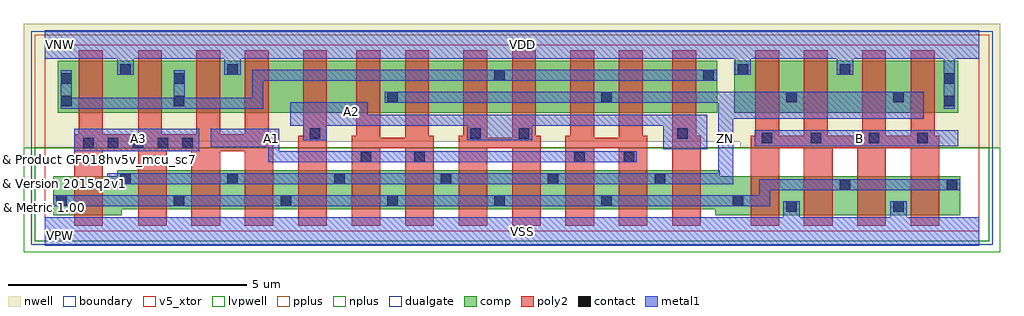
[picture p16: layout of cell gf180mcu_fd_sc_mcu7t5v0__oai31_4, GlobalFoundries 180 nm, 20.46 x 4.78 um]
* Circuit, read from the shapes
.subckt gf180mcu_fd_sc_mcu7t5v0__oai31_4 A1 A2 A3 B VDD VNW VSS ZN
XM1 ZN A3 n1 VSUBS nfet_05v0 w=0.82u l=0.6u m=4
XM2 ZN A2 n1 VSUBS nfet_05v0 w=0.82u l=0.6u m=4
XM3 n1 A1 ZN VSUBS nfet_05v0 w=0.82u l=0.6u m=4
XM4 VSS B n1 VSUBS nfet_05v0 w=0.82u l=0.6u m=4
XM5 VDD A3 n2 VNW pfet_05v0 w=1.095u l=0.5u m=3
XM6 n3 A3 VDD VNW pfet_05v0 w=1.095u l=0.5u
XM7 n4 A2 n3 VNW pfet_05v0 w=1.095u l=0.5u
XM8 ZN A1 n4 VNW pfet_05v0 w=1.095u l=0.5u
XM9 n5 A1 ZN VNW pfet_05v0 w=1.095u l=0.5u
XM10 n2 A2 n5 VNW pfet_05v0 w=1.095u l=0.5u
XM11 n6 A2 n2 VNW pfet_05v0 w=1.095u l=0.5u
XM12 ZN A1 n6 VNW pfet_05v0 w=1.095u l=0.5u
XM13 n7 A1 ZN VNW pfet_05v0 w=1.095u l=0.5u
XM14 n2 A2 n7 VNW pfet_05v0 w=1.095u l=0.5u
XM15 ZN B VDD VNW pfet_05v0 w=1.095u l=0.5u m=4
.ends

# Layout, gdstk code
import gdstk
lib = gdstk.Library(unit=1e-6, precision=1e-09)
def R(c, l, rs):  # rectangles x0, y0, x1, y1
    for r in rs: c.add(gdstk.rectangle(r[:2], r[2:], *l))
def A(c, l, x, y, w, h, nx, ny, dx, dy):  # array of equal rectangles
    R(c, l, [(x+i*dx, y+j*dy, x+i*dx+w, y+j*dy+h) for i in range(nx) for j in range(ny)])
def P(c, l, *ps):  # polygons
    for p in ps: c.add(gdstk.Polygon(p, *l))
boundary = (0, 0)
nwell = (21, 0)
comp = (22, 0)
poly2 = (30, 0)
pplus = (31, 0)
nplus = (32, 0)
contact = (33, 0)
metal1 = (34, 0)
dualgate = (55, 0)
v5_xtor = (112, 1)
lvpwell = (204, 0)

gf180mcu_fd_sc_mcu7t5v0_ = lib.new_cell('gf180mcu_fd_sc_mcu7t5v0__oai31_4')
R(gf180mcu_fd_sc_mcu7t5v0_, boundary, [(0,0,19.6,3.92)])
P(gf180mcu_fd_sc_mcu7t5v0_, nwell, [(-0.43,1.76),(-0.43,4.35),(20.03,4.35),(20.03,1.76),(14.58,1.76),(14.58,1.885),(1.095,1.885),(1.095,1.76)])
R(gf180mcu_fd_sc_mcu7t5v0_, comp, [(0.28,2.485,14.1,3.58), (14.46,2.485,19.15,3.58)])
P(gf180mcu_fd_sc_mcu7t5v0_, comp, [(0.18,0.34),(0.18,1.16),(1.52,1.16),(1.52,1.285),(14.16,1.285),(14.16,1.16),(19.2,1.16),(19.2,0.34),(14.06,0.34),(14.06,0.465),(1.62,0.465),(1.62,0.34)])
P(gf180mcu_fd_sc_mcu7t5v0_, poly2, [(0.62,0.12),(0.62,2.04),(0.72,2.04),(0.72,3.8),(1.22,3.8),(1.22,2.04),(1.96,2.04),(1.96,3.8),(2.46,3.8),(2.46,2.04),(3.18,2.04),(3.18,3.8),(3.68,3.8),(3.68,2.04),(4.2,2.04),(4.2,3.8),(4.7,3.8),(4.7,2.04),(4.8,2.04),(4.8,0.12),(4.2,0.12),(4.2,1.68),(3.68,1.68),(3.68,0.12),(3.08,0.12),(3.08,1.68),(2.56,1.68),(2.56,0.12),(1.96,0.12),(1.96,1.68),(1.22,1.68),(1.22,0.12)],
  [(5.32,0.12),(5.32,2.01),(5.42,2.01),(5.42,3.8),(5.92,3.8),(5.92,0.12)],
  [(6.44,0.12),(6.44,2.01),(6.54,2.01),(6.54,3.8),(7.04,3.8),(7.04,1.97),(7.56,1.97),(7.56,3.8),(8.06,3.8),(8.06,2.01),(8.16,2.01),(8.16,0.12),(7.56,0.12),(7.56,1.74),(7.04,1.74),(7.04,0.12)],
  [(8.68,0.12),(8.68,2.01),(8.78,2.01),(8.78,3.8),(9.28,3.8),(9.28,1.97),(9.8,1.97),(9.8,3.8),(10.3,3.8),(10.3,2.01),(10.4,2.01),(10.4,0.12),(9.8,0.12),(9.8,1.74),(9.28,1.74),(9.28,0.12)],
  [(10.92,0.12),(10.92,2.01),(11.02,2.01),(11.02,3.8),(11.52,3.8),(11.52,1.97),(12.04,1.97),(12.04,3.8),(12.54,3.8),(12.54,2.01),(12.64,2.01),(12.64,0.12),(12.04,0.12),(12.04,1.74),(11.52,1.74),(11.52,0.12)],
  [(13.16,0.12),(13.16,3.8),(13.66,3.8),(13.66,2.01),(13.76,2.01),(13.76,0.12)],
  [(14.8,0.12),(14.8,2.01),(14.9,2.01),(14.9,3.8),(15.4,3.8),(15.4,2.01),(15.92,2.01),(15.92,3.8),(16.42,3.8),(16.42,2.01),(17.14,2.01),(17.14,3.8),(17.64,3.8),(17.64,2.01),(18.16,2.01),(18.16,3.8),(18.66,3.8),(18.66,2.01),(18.76,2.01),(18.76,0.12),(18.16,0.12),(18.16,1.74),(17.64,1.74),(17.64,0.12),(17.04,0.12),(17.04,1.74),(16.52,1.74),(16.52,0.12),(15.92,0.12),(15.92,1.74),(15.4,1.74),(15.4,0.12)])
R(gf180mcu_fd_sc_mcu7t5v0_, pplus, [(-0.2,1.76,19.8,4.12)])
R(gf180mcu_fd_sc_mcu7t5v0_, nplus, [(-0.2,-0.2,19.8,1.76)])
A(gf180mcu_fd_sc_mcu7t5v0_, contact, 2.71, 0.535, 0.22, 0.22, 5, 1, 2.24, 0)
A(gf180mcu_fd_sc_mcu7t5v0_, contact, 1.59, 0.995, 0.22, 0.22, 6, 1, 2.24, 0)
A(gf180mcu_fd_sc_mcu7t5v0_, contact, 0.81, 1.75, 0.22, 0.22, 5, 1, 0.52, 0)
R(gf180mcu_fd_sc_mcu7t5v0_, contact, [(15.55,0.41,15.77,0.63), (17.79,0.41,18.01,0.63), (0.25,0.535,0.47,0.755), (14.43,0.535,14.65,0.755), (16.67,0.87,16.89,1.09), (18.91,0.87,19.13,1.09), (6.63,1.455,6.85,1.675), (7.75,1.455,7.97,1.675), (11.11,1.455,11.33,1.675), (12.14,1.455,12.36,1.675), (15.04,1.85,15.26,2.07), (16.06,1.85,16.28,2.07), (17.28,1.85,17.5,2.07), (18.3,1.85,18.52,2.07), (5.56,1.94,5.78,2.16), (8.92,1.94,9.14,2.16), (9.94,1.94,10.16,2.16), (13.26,1.94,13.48,2.16), (0.35,2.63,0.57,2.85), (2.71,2.63,2.93,2.85), (18.86,2.63,19.08,2.85), (7.19,2.705,7.41,2.925), (11.67,2.705,11.89,2.925), (15.55,2.705,15.77,2.925), (17.79,2.705,18.01,2.925), (0.35,3.1,0.57,3.32), (2.71,3.1,2.93,3.32), (18.86,3.1,19.08,3.32), (9.43,3.165,9.65,3.385), (13.81,3.165,14.03,3.385), (1.59,3.29,1.81,3.51), (3.83,3.29,4.05,3.51), (14.53,3.29,14.75,3.51), (16.67,3.29,16.89,3.51)])
R(gf180mcu_fd_sc_mcu7t5v0_, metal1, [(0.62,1.68,3.24,2.15), (14.89,1.785,19.15,2.12)])
P(gf180mcu_fd_sc_mcu7t5v0_, metal1, [(4.69,1.45),(4.69,1.77),(3.48,1.77),(3.48,2.15),(4.92,2.15),(4.92,1.68),(12.42,1.68),(12.42,1.45)],
  [(12.97,1.725),(12.97,2.22),(10.22,2.22),(10.22,1.91),(8.86,1.91),(8.86,2.22),(5.92,2.22),(5.92,1.91),(5.42,1.91),(5.42,2.22),(5.15,2.22),(5.15,2.71),(6.775,2.71),(6.775,2.45),(13.89,2.45),(13.89,1.725)],
  [(0.345,2.57),(0.345,3.38),(0.575,3.38),(0.575,2.8),(2.705,2.8),(2.705,3.38),(2.935,3.38),(2.935,2.8),(4.36,2.8),(4.36,3.39),(14.1,3.39),(14.1,3.16),(4.59,3.16),(4.59,2.57)],
  [(1.31,0.99),(1.31,1.22),(14.12,1.22),(14.12,2.7),(7.13,2.7),(7.13,2.93),(18.43,2.93),(18.43,2.36),(14.44,2.36),(14.44,0.99)],
  [(0.18,0.53),(0.18,0.76),(14.98,0.76),(14.98,1.095),(19.2,1.095),(19.2,0.865),(15.21,0.865),(15.21,0.53)],
  [(0,-0.3),(0,0.3),(15.49,0.3),(15.49,0.635),(15.83,0.635),(15.83,0.3),(17.73,0.3),(17.73,0.635),(18.07,0.635),(18.07,0.3),(19.6,0.3),(19.6,-0.3)],
  [(18.855,2.57),(18.855,3.62),(16.95,3.62),(16.95,3.285),(16.61,3.285),(16.61,3.62),(14.81,3.62),(14.81,3.285),(14.47,3.285),(14.47,3.62),(4.11,3.62),(4.11,3.285),(3.77,3.285),(3.77,3.62),(1.87,3.62),(1.87,3.285),(1.53,3.285),(1.53,3.62),(0,3.62),(0,4.22),(19.6,4.22),(19.6,3.62),(19.085,3.62),(19.085,2.57)])
R(gf180mcu_fd_sc_mcu7t5v0_, dualgate, [(-0.28,-0.28,19.88,4.2)])
R(gf180mcu_fd_sc_mcu7t5v0_, v5_xtor, [(0,0,19.6,3.92)])
R(gf180mcu_fd_sc_mcu7t5v0_, lvpwell, [(-0.43,-0.43,20.03,1.76)])
gf180mcu_fd_sc_mcu7t5v0_.add(gdstk.Label('A3', (1.96,1.96), layer=34, texttype=10))
gf180mcu_fd_sc_mcu7t5v0_.add(gdstk.Label('B', (17.08,1.96), layer=34, texttype=10))
gf180mcu_fd_sc_mcu7t5v0_.add(gdstk.Label('VDD', (10.02,3.92), layer=34, texttype=10))
gf180mcu_fd_sc_mcu7t5v0_.add(gdstk.Label('VSS', (10.02,0), layer=34, texttype=10))
gf180mcu_fd_sc_mcu7t5v0_.add(gdstk.Label('ZN', (14.28,1.96), layer=34, texttype=10))
gf180mcu_fd_sc_mcu7t5v0_.add(gdstk.Label('A1', (4.76,1.96), layer=34, texttype=10))
gf180mcu_fd_sc_mcu7t5v0_.add(gdstk.Label('A2', (6.44,2.52), layer=34, texttype=10))
gf180mcu_fd_sc_mcu7t5v0_.add(gdstk.Label('& Vendor GLOBALFOUNDRIES', (0,2), layer=63, texttype=63))
gf180mcu_fd_sc_mcu7t5v0_.add(gdstk.Label('& Product GF018hv5v_mcu_sc7', (0,1.5), layer=63, texttype=63))
gf180mcu_fd_sc_mcu7t5v0_.add(gdstk.Label('& Version 2015q2v1', (0,1), layer=63, texttype=63))
gf180mcu_fd_sc_mcu7t5v0_.add(gdstk.Label('& Metric 1.00', (0,0.5), layer=63, texttype=63))
gf180mcu_fd_sc_mcu7t5v0_.add(gdstk.Label('VNW', (0.345,3.92), layer=21, texttype=10))
gf180mcu_fd_sc_mcu7t5v0_.add(gdstk.Label('VPW', (0.34,-0.085), layer=204, texttype=10))

lib.write_gds('gf180mcu_fd_sc_mcu7t5v0__oai31_4.gds')
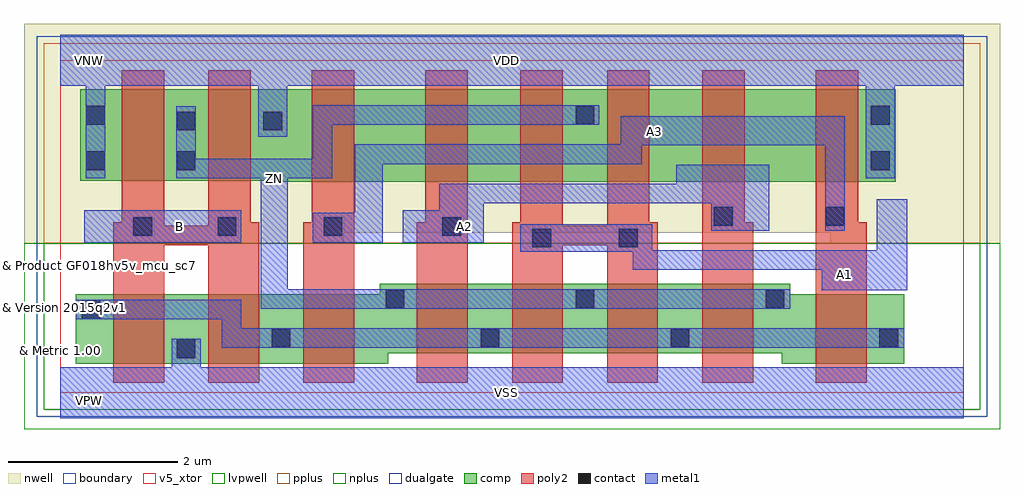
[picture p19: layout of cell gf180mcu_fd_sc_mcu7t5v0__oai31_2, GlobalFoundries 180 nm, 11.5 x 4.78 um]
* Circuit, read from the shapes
.subckt gf180mcu_fd_sc_mcu7t5v0__oai31_2 A1 A2 A3 B VDD VNW VSS ZN
XM1 VSS B n1 VSUBS nfet_05v0 w=0.82u l=0.6u m=2
XM2 ZN A3 n1 VSUBS nfet_05v0 w=0.82u l=0.6u m=2
XM3 n1 A2 ZN VSUBS nfet_05v0 w=0.82u l=0.6u m=2
XM4 ZN A1 n1 VSUBS nfet_05v0 w=0.82u l=0.6u m=2
XM5 ZN B VDD VNW pfet_05v0 w=1.08u l=0.5u m=2
XM6 n2 A3 VDD VNW pfet_05v0 w=1.095u l=0.5u
XM7 n3 A2 n2 VNW pfet_05v0 w=1.095u l=0.5u
XM8 ZN A1 n3 VNW pfet_05v0 w=1.095u l=0.5u
XM9 n4 A1 ZN VNW pfet_05v0 w=1.095u l=0.5u
XM10 n5 A2 n4 VNW pfet_05v0 w=1.095u l=0.5u
XM11 VDD A3 n5 VNW pfet_05v0 w=1.095u l=0.5u
.ends

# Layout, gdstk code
import gdstk
lib = gdstk.Library(unit=1e-6, precision=1e-09)
def R(c, l, rs):  # rectangles x0, y0, x1, y1
    for r in rs: c.add(gdstk.rectangle(r[:2], r[2:], *l))
def A(c, l, x, y, w, h, nx, ny, dx, dy):  # array of equal rectangles
    R(c, l, [(x+i*dx, y+j*dy, x+i*dx+w, y+j*dy+h) for i in range(nx) for j in range(ny)])
def P(c, l, *ps):  # polygons
    for p in ps: c.add(gdstk.Polygon(p, *l))
boundary = (0, 0)
nwell = (21, 0)
comp = (22, 0)
poly2 = (30, 0)
pplus = (31, 0)
nplus = (32, 0)
contact = (33, 0)
metal1 = (34, 0)
dualgate = (55, 0)
v5_xtor = (112, 1)
lvpwell = (204, 0)

gf180mcu_fd_sc_mcu7t5v0_ = lib.new_cell('gf180mcu_fd_sc_mcu7t5v0__oai31_2')
R(gf180mcu_fd_sc_mcu7t5v0_, boundary, [(0,0,10.64,3.92)])
P(gf180mcu_fd_sc_mcu7t5v0_, nwell, [(-0.43,1.76),(-0.43,4.35),(11.07,4.35),(11.07,1.76),(9.07,1.76),(9.07,1.885),(3.34,1.885),(3.34,1.76)])
P(gf180mcu_fd_sc_mcu7t5v0_, comp, [(2.56,2.485),(2.56,2.5),(0.23,2.5),(0.23,3.58),(9.84,3.58),(9.84,2.485)],
  [(0.18,0.34),(0.18,1.16),(3.76,1.16),(3.76,1.285),(8.6,1.285),(8.6,1.16),(9.94,1.16),(9.94,0.34),(8.5,0.34),(8.5,0.465),(3.86,0.465),(3.86,0.34)])
P(gf180mcu_fd_sc_mcu7t5v0_, poly2, [(0.62,0.12),(0.62,2.01),(0.72,2.01),(0.72,3.8),(1.22,3.8),(1.22,1.97),(1.74,1.97),(1.74,3.8),(2.24,3.8),(2.24,2.01),(2.34,2.01),(2.34,0.12),(1.74,0.12),(1.74,1.74),(1.22,1.74),(1.22,0.12)],
  [(2.86,0.12),(2.86,2.01),(2.96,2.01),(2.96,3.8),(3.46,3.8),(3.46,0.12)],
  [(4.2,0.12),(4.2,2.01),(4.3,2.01),(4.3,3.8),(4.8,3.8),(4.8,0.12)],
  [(5.32,0.12),(5.32,2.01),(5.42,2.01),(5.42,3.8),(5.92,3.8),(5.92,1.97),(6.44,1.97),(6.44,3.8),(6.94,3.8),(6.94,2.01),(7.04,2.01),(7.04,0.12),(6.44,0.12),(6.44,1.74),(5.92,1.74),(5.92,0.12)],
  [(7.56,0.12),(7.56,3.8),(8.06,3.8),(8.06,2.01),(8.16,2.01),(8.16,0.12)],
  [(8.9,0.12),(8.9,3.8),(9.4,3.8),(9.4,2.01),(9.5,2.01),(9.5,0.12)])
R(gf180mcu_fd_sc_mcu7t5v0_, pplus, [(-0.2,1.76,10.84,4.12)])
R(gf180mcu_fd_sc_mcu7t5v0_, nplus, [(-0.2,-0.2,10.84,1.76)])
A(gf180mcu_fd_sc_mcu7t5v0_, contact, 3.83, 0.995, 0.22, 0.22, 3, 1, 2.24, 0)
R(gf180mcu_fd_sc_mcu7t5v0_, contact, [(1.37,0.41,1.59,0.63), (2.49,0.535,2.71,0.755), (4.95,0.535,5.17,0.755), (7.19,0.535,7.41,0.755), (9.65,0.535,9.87,0.755), (0.25,0.87,0.47,1.09), (5.56,1.715,5.78,1.935), (6.58,1.715,6.8,1.935), (0.86,1.85,1.08,2.07), (1.85,1.85,2.07,2.07), (3.1,1.85,3.32,2.07), (4.5,1.85,4.72,2.07), (7.7,1.97,7.92,2.19), (9.015,1.97,9.235,2.19), (0.3,2.625,0.52,2.845), (1.37,2.625,1.59,2.845), (9.55,2.625,9.77,2.845), (1.37,3.095,1.59,3.315), (2.39,3.095,2.61,3.315), (0.3,3.16,0.52,3.38), (9.55,3.16,9.77,3.38), (6.07,3.165,6.29,3.385)])
R(gf180mcu_fd_sc_mcu7t5v0_, metal1, [(0.28,1.77,2.13,2.15)])
P(gf180mcu_fd_sc_mcu7t5v0_, metal1, [(4.03,1.77),(4.03,2.15),(4.46,2.15),(4.46,2.465),(7.255,2.465),(7.255,2.69),(8.35,2.69),(8.35,1.91),(7.67,1.91),(7.67,2.235),(4.99,2.235),(4.99,1.77)],
  [(2.36,0.99),(2.36,2.53),(1.365,2.53),(1.365,3.375),(1.595,3.375),(1.595,2.76),(2.97,2.76),(2.97,3.39),(6.35,3.39),(6.35,3.16),(3.2,3.16),(3.2,2.53),(2.68,2.53),(2.68,1.22),(8.6,1.22),(8.6,0.99)],
  [(2.97,1.77),(2.97,2.12),(3.47,2.12),(3.47,2.93),(6.6,2.93),(6.6,3.26),(9.24,3.26),(9.24,1.91),(9.01,1.91),(9.01,2.92),(6.85,2.92),(6.85,2.695),(3.8,2.695),(3.8,1.77)],
  [(1.9,0.53),(1.9,0.865),(0.18,0.865),(0.18,1.095),(2.13,1.095),(2.13,0.76),(9.94,0.76),(9.94,0.53)],
  [(8.97,1.21),(8.97,1.45),(6.745,1.45),(6.745,1.665),(5.42,1.665),(5.42,1.985),(6.975,1.985),(6.975,1.68),(9.62,1.68),(9.62,2.28),(9.98,2.28),(9.98,1.21)],
  [(0,-0.3),(0,0.3),(1.31,0.3),(1.31,0.635),(1.65,0.635),(1.65,0.3),(10.64,0.3),(10.64,-0.3)],
  [(0.295,2.53),(0.295,3.62),(0,3.62),(0,4.22),(10.64,4.22),(10.64,3.62),(9.83,3.62),(9.83,2.53),(9.49,2.53),(9.49,3.62),(2.67,3.62),(2.67,3.02),(2.33,3.02),(2.33,3.62),(0.525,3.62),(0.525,2.53)])
R(gf180mcu_fd_sc_mcu7t5v0_, dualgate, [(-0.28,-0.28,10.92,4.2)])
R(gf180mcu_fd_sc_mcu7t5v0_, v5_xtor, [(0,0,10.64,3.92)])
R(gf180mcu_fd_sc_mcu7t5v0_, lvpwell, [(-0.43,-0.43,11.07,1.76)])
gf180mcu_fd_sc_mcu7t5v0_.add(gdstk.Label('A2', (4.76,1.96), layer=34, texttype=10))
gf180mcu_fd_sc_mcu7t5v0_.add(gdstk.Label('A3', (7,3.08), layer=34, texttype=10))
gf180mcu_fd_sc_mcu7t5v0_.add(gdstk.Label('B', (1.4,1.96), layer=34, texttype=10))
gf180mcu_fd_sc_mcu7t5v0_.add(gdstk.Label('VDD', (5.26,3.92), layer=34, texttype=10))
gf180mcu_fd_sc_mcu7t5v0_.add(gdstk.Label('VSS', (5.26,0), layer=34, texttype=10))
gf180mcu_fd_sc_mcu7t5v0_.add(gdstk.Label('ZN', (2.52,2.52), layer=34, texttype=10))
gf180mcu_fd_sc_mcu7t5v0_.add(gdstk.Label('A1', (9.24,1.4), layer=34, texttype=10))
gf180mcu_fd_sc_mcu7t5v0_.add(gdstk.Label('& Vendor GLOBALFOUNDRIES', (0,2), layer=63, texttype=63))
gf180mcu_fd_sc_mcu7t5v0_.add(gdstk.Label('& Product GF018hv5v_mcu_sc7', (0,1.5), layer=63, texttype=63))
gf180mcu_fd_sc_mcu7t5v0_.add(gdstk.Label('& Version 2015q2v1', (0,1), layer=63, texttype=63))
gf180mcu_fd_sc_mcu7t5v0_.add(gdstk.Label('& Metric 1.00', (0,0.5), layer=63, texttype=63))
gf180mcu_fd_sc_mcu7t5v0_.add(gdstk.Label('VNW', (0.345,3.92), layer=21, texttype=10))
gf180mcu_fd_sc_mcu7t5v0_.add(gdstk.Label('VPW', (0.34,-0.085), layer=204, texttype=10))

lib.write_gds('gf180mcu_fd_sc_mcu7t5v0__oai31_2.gds')
